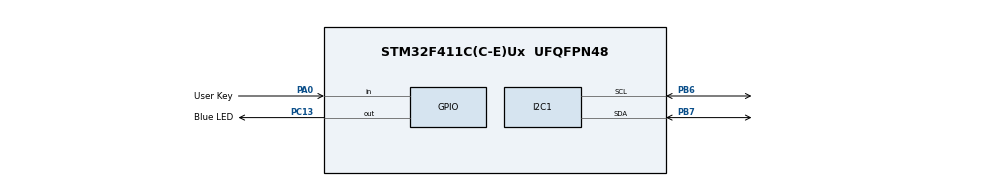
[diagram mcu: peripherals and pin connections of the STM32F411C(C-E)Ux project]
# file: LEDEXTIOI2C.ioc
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I2C1.I2C_Mode=I2C_Fast
Mcu.Family=STM32F4
Mcu.Name=STM32F411C(C-E)Ux
Mcu.Package=UFQFPN48
NVIC.PriorityGroup=NVIC_PRIORITYGROUP_4
PA0-WKUP.GPIO_Label=User Key
PA0-WKUP.GPIO_PuPd=GPIO_PULLUP
PA0-WKUP.Signal=GPIO_Input
PA13.Mode=Serial_Wire
PA13.Signal=SYS_JTMS-SWDIO
PA14.Mode=Serial_Wire
PA14.Signal=SYS_JTCK-SWCLK
PB6.Mode=I2C
PB6.Signal=I2C1_SCL
PB7.Mode=I2C
PB7.Signal=I2C1_SDA
PC13-ANTI_TAMP.GPIO_Label=Blue LED
PC13-ANTI_TAMP.GPIO_ModeDefaultOutputPP=GPIO_MODE_OUTPUT_OD
PC13-ANTI_TAMP.GPIO_PuPd=GPIO_NOPULL
PC13-ANTI_TAMP.PinState=GPIO_PIN_SET
PC13-ANTI_TAMP.Signal=GPIO_Output
PC14-OSC32_IN.Mode=LSE-External-Oscillator
PC14-OSC32_IN.Signal=RCC_OSC32_IN
PC15-OSC32_OUT.Mode=LSE-External-Oscillator
PC15-OSC32_OUT.Signal=RCC_OSC32_OUT
PH0\ -\ OSC_IN.Mode=HSE-External-Oscillator
PH0\ -\ OSC_IN.Signal=RCC_OSC_IN
PH1\ -\ OSC_OUT.Mode=HSE-External-Oscillator
PH1\ -\ OSC_OUT.Signal=RCC_OSC_OUT
ProjectManager.HeapSize=0x200
ProjectManager.StackSize=0x400
ProjectManager.TargetToolchain=CMake
RCC.48MHZClocksFreq_Value=50000000
RCC.AHBFreq_Value=100000000
RCC.APB1CLKDivider=RCC_HCLK_DIV2
RCC.APB1Freq_Value=50000000
RCC.APB1TimFreq_Value=100000000
RCC.APB2Freq_Value=100000000
RCC.APB2TimFreq_Value=100000000
RCC.CortexFreq_Value=100000000
RCC.HCLKFreq_Value=100000000
RCC.HSE_VALUE=25000000
RCC.HSI_VALUE=16000000
RCC.PLLM=12
RCC.PLLN=96
RCC.PLLSourceVirtual=RCC_PLLSOURCE_HSE
RCC.SYSCLKFreq_VALUE=100000000
RCC.SYSCLKSource=RCC_SYSCLKSOURCE_PLLCLK
RCC.VCOOutputFreq_Value=200000000
board=custom

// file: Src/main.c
/* USER CODE BEGIN Header */
/**
 ******************************************************************************
 * @file           : main.c
 * @brief          : Main program body
 ******************************************************************************
 * @attention
 *
 * Copyright (c) 2025 STMicroelectronics.
 * All rights reserved.
 *
 * This software is licensed under terms that can be found in the LICENSE file
 * in the root directory of this software component.
 * If no LICENSE file comes with this software, it is provided AS-IS.
 *
 ******************************************************************************
 */
/* USER CODE END Header */
#include "main.h"

/* USER CODE BEGIN Includes */
#include "ssd1306.h"
#include "ssd1306_fonts.h" // Include the fonts header file located at
#include "ssd1306_tests.h"
/* USER CODE END Includes */

I2C_HandleTypeDef hi2c1;

void SystemClock_Config(void);
static void MX_GPIO_Init(void);
static void MX_I2C1_Init(void);

int main(void)
{

  /* USER CODE BEGIN 1 */
  // char myText[] = "Hello, SSD1306!";
  // char retVal;
  /* USER CODE END 1 */

  /* MCU Configuration--------------------------------------------------------*/

  /* Reset of all peripherals, Initializes the Flash interface and the Systick. */
  HAL_Init();

  /* Configure the system clock */
  SystemClock_Config();

  /* Initialize all configured peripherals */
  MX_GPIO_Init();
  MX_I2C1_Init();
  /* USER CODE BEGIN 2 */
  ssd1306_Init();
  // ssd1306_Fill(White);
  // ssd1306_UpdateScreen();

  //  ssd1306_SetCursor(5, 5);
  //  retVal = ssd1306_WriteString(myText, Font_7x10, White);
  //  ssd1306_UpdateScreen();

  // Run tests
  // ssd1306_TestAll();

  // ssd1306_TestBorder();
  // ssd1306_TestFonts1();
  // ssd1306_TestFonts2();
  // ssd1306_TestFPS();
  // ssd1306_TestLine();
  // ssd1306_TestRectangle();
  // ssd1306_TestRectangleFill();
  // ssd1306_TestRectangleInvert();
  // ssd1306_TestCircle();
  // ssd1306_TestArc();
  // ssd1306_TestPolyline();
  // ssd1306_TestDrawBitmap();
  /* USER CODE END 2 */

  /* Infinite loop */
  while (1) {

  }
}

void SystemClock_Config(void)
{
  RCC_OscInitTypeDef RCC_OscInitStruct = {0};
  RCC_ClkInitTypeDef RCC_ClkInitStruct = {0};

  /** Configure the main internal regulator output voltage
  */
  __HAL_RCC_PWR_CLK_ENABLE();
  __HAL_PWR_VOLTAGESCALING_CONFIG(PWR_REGULATOR_VOLTAGE_SCALE1);

  /** Initializes the RCC Oscillators according to the specified parameters
  * in the RCC_OscInitTypeDef structure.
  */
  RCC_OscInitStruct.OscillatorType = RCC_OSCILLATORTYPE_HSI;
  RCC_OscInitStruct.HSIState = RCC_HSI_ON;
  RCC_OscInitStruct.HSICalibrationValue = RCC_HSICALIBRATION_DEFAULT;
  RCC_OscInitStruct.PLL.PLLState = RCC_PLL_ON;
  RCC_OscInitStruct.PLL.PLLSource = RCC_PLLSOURCE_HSI;
  RCC_OscInitStruct.PLL.PLLM = 8;
  RCC_OscInitStruct.PLL.PLLN = 72;
  RCC_OscInitStruct.PLL.PLLP = RCC_PLLP_DIV2;
  RCC_OscInitStruct.PLL.PLLQ = 4;
  if (HAL_RCC_OscConfig(&RCC_OscInitStruct) != HAL_OK)
  {
    Error_Handler();
  }

  /** Initializes the CPU, AHB and APB buses clocks
  */
  RCC_ClkInitStruct.ClockType = RCC_CLOCKTYPE_HCLK|RCC_CLOCKTYPE_SYSCLK
                              |RCC_CLOCKTYPE_PCLK1|RCC_CLOCKTYPE_PCLK2;
  RCC_ClkInitStruct.SYSCLKSource = RCC_SYSCLKSOURCE_PLLCLK;
  RCC_ClkInitStruct.AHBCLKDivider = RCC_SYSCLK_DIV1;
  RCC_ClkInitStruct.APB1CLKDivider = RCC_HCLK_DIV2;
  RCC_ClkInitStruct.APB2CLKDivider = RCC_HCLK_DIV1;

  if (HAL_RCC_ClockConfig(&RCC_ClkInitStruct, FLASH_LATENCY_2) != HAL_OK)
  {
    Error_Handler();
  }
}

static void MX_I2C1_Init(void)
{

  hi2c1.Instance = I2C1;
  hi2c1.Init.ClockSpeed = 400000;
  hi2c1.Init.DutyCycle = I2C_DUTYCYCLE_2;
  hi2c1.Init.OwnAddress1 = 0;
  hi2c1.Init.AddressingMode = I2C_ADDRESSINGMODE_7BIT;
  hi2c1.Init.DualAddressMode = I2C_DUALADDRESS_DISABLE;
  hi2c1.Init.OwnAddress2 = 0;
  hi2c1.Init.GeneralCallMode = I2C_GENERALCALL_DISABLE;
  hi2c1.Init.NoStretchMode = I2C_NOSTRETCH_DISABLE;
  if (HAL_I2C_Init(&hi2c1) != HAL_OK)
  {
    Error_Handler();
  }

}

static void MX_GPIO_Init(void)
{
  GPIO_InitTypeDef GPIO_InitStruct = {0};

  /* GPIO Ports Clock Enable */
  __HAL_RCC_GPIOC_CLK_ENABLE();
  __HAL_RCC_GPIOH_CLK_ENABLE();
  __HAL_RCC_GPIOA_CLK_ENABLE();
  __HAL_RCC_GPIOB_CLK_ENABLE();

  /*Configure GPIO pin Output Level */
  HAL_GPIO_WritePin(Blue_LED_GPIO_Port, Blue_LED_Pin, GPIO_PIN_SET);

  /*Configure GPIO pin : Blue_LED_Pin */
  GPIO_InitStruct.Pin = Blue_LED_Pin;
  GPIO_InitStruct.Mode = GPIO_MODE_OUTPUT_OD;
  GPIO_InitStruct.Pull = GPIO_NOPULL;
  GPIO_InitStruct.Speed = GPIO_SPEED_FREQ_LOW;
  HAL_GPIO_Init(Blue_LED_GPIO_Port, &GPIO_InitStruct);

  /*Configure GPIO pin : User_Key_Pin */
  GPIO_InitStruct.Pin = User_Key_Pin;
  GPIO_InitStruct.Mode = GPIO_MODE_INPUT;
  GPIO_InitStruct.Pull = GPIO_PULLUP;
  HAL_GPIO_Init(User_Key_GPIO_Port, &GPIO_InitStruct);

}

void Error_Handler(void)
{
  __disable_irq();
  while (1) {
  }
}
#ifdef USE_FULL_ASSERT
/**
  * @brief  Reports the name of the source file and the source line number
  *         where the assert_param error has occurred.
  * @param  file: pointer to the source file name
  * @param  line: assert_param error line source number
  * @retval None
  */
void assert_failed(uint8_t *file, uint32_t line)
{
  /* USER CODE BEGIN 6 */
  /* User can add his own implementation to report the file name and line
     number, ex: printf("Wrong parameters value: file %s on line %d\r\n", file,
     line) */
  /* USER CODE END 6 */
}
#endif /* USE_FULL_ASSERT */
